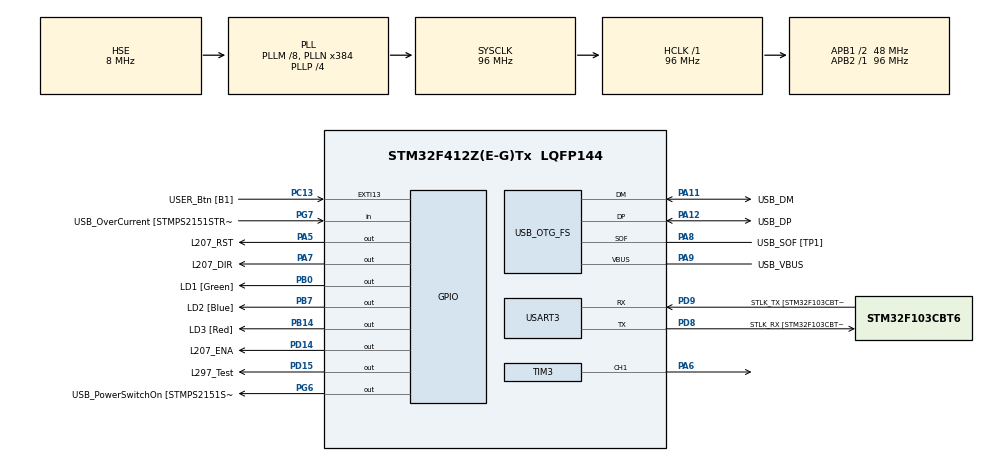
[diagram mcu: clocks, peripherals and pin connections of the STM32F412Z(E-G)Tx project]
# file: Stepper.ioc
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Mcu.Family=STM32F4
Mcu.Name=STM32F412Z(E-G)Tx
Mcu.Package=LQFP144
NVIC.PriorityGroup=NVIC_PRIORITYGROUP_4
NVIC.TIM3_IRQn=true\:0\:0\:false\:false\:true\:true\:true\:true
PA10.GPIO_Label=USB_ID
PA10.Signal=USB_OTG_FS_ID
PA11.GPIO_Label=USB_DM
PA11.Mode=Device_Only
PA11.Signal=USB_OTG_FS_DM
PA12.GPIO_Label=USB_DP
PA12.Mode=Device_Only
PA12.Signal=USB_OTG_FS_DP
PA13.GPIO_Label=TMS
PA13.Mode=Serial_Wire
PA13.Signal=SYS_JTMS-SWDIO
PA14.GPIO_Label=TCK
PA14.Mode=Serial_Wire
PA14.Signal=SYS_JTCK-SWCLK
PA5.GPIO_Label=L207_RST
PA5.Signal=GPIO_Output
PA6.Signal=S_TIM3_CH1
PA7.GPIO_Label=L207_DIR
PA7.Signal=GPIO_Output
PA8.GPIO_Label=USB_SOF [TP1]
PA8.Mode=Activate_SOF_FS
PA8.Signal=USB_OTG_FS_SOF
PA9.GPIO_Label=USB_VBUS
PA9.Mode=Activate_VBUS
PA9.Signal=USB_OTG_FS_VBUS
PB0.GPIO_Label=LD1 [Green]
PB0.Signal=GPIO_Output
PB14.GPIO_Label=LD3 [Red]
PB14.Signal=GPIO_Output
PB3.GPIO_Label=SWO
PB3.Signal=SYS_JTDO-SWO
PB7.GPIO_Label=LD2 [Blue]
PB7.Signal=GPIO_Output
PC13.GPIO_Label=USER_Btn [B1]
PC13.Signal=GPXTI13
PC14-OSC32_IN.Mode=LSE-External-Oscillator
PC14-OSC32_IN.Signal=RCC_OSC32_IN
PC15-OSC32_OUT.Mode=LSE-External-Oscillator
PC15-OSC32_OUT.Signal=RCC_OSC32_OUT
PD14.GPIO_Label=L207_ENA
PD14.Signal=GPIO_Output
PD15.GPIO_Label=L297_Test
PD15.Signal=GPIO_Output
PD8.GPIO_Label=STLK_RX [STM32F103CBT6_PA3]
PD8.Mode=Asynchronous
PD8.Signal=USART3_TX
PD9.GPIO_Label=STLK_TX [STM32F103CBT6_PA2]
PD9.Mode=Asynchronous
PD9.Signal=USART3_RX
PG6.GPIO_Label=USB_PowerSwitchOn [STMPS2151STR_EN]
PG6.Signal=GPIO_Output
PG7.GPIO_Label=USB_OverCurrent [STMPS2151STR_FAULT]
PG7.Signal=GPIO_Input
PH0\ -\ OSC_IN.GPIO_Label=MCO
PH0\ -\ OSC_IN.Mode=HSE-External-Clock-Source
PH0\ -\ OSC_IN.Signal=RCC_OSC_IN
PH1\ -\ OSC_OUT.Mode=HSE-External-Clock-Source
PH1\ -\ OSC_OUT.Signal=RCC_OSC_OUT
ProjectManager.HeapSize=0x400
ProjectManager.StackSize=0x800
ProjectManager.TargetToolchain=STM32CubeIDE
RCC.48MHZClocksFreq_Value=24000000
RCC.AHBFreq_Value=96000000
RCC.APB1CLKDivider=RCC_HCLK_DIV2
RCC.APB1Freq_Value=48000000
RCC.APB1TimFreq_Value=96000000
RCC.APB2Freq_Value=96000000
RCC.APB2TimFreq_Value=96000000
RCC.CortexFreq_Value=96000000
RCC.HCLKFreq_Value=96000000
RCC.HSE_VALUE=8000000
RCC.HSI_VALUE=16000000
RCC.PLLM=8
RCC.PLLMUL=RCC_PLL_MUL9
RCC.PLLN=384
RCC.PLLP=RCC_PLLP_DIV4
RCC.PLLQ=8
RCC.PRESCALERUSB=RCC_USBCLKSOURCE_PLL_DIV1_5
RCC.SYSCLKFreq_VALUE=96000000
RCC.SYSCLKSource=RCC_SYSCLKSOURCE_PLLCLK
RCC.SYSCLKSourceVirtual=RCC_SYSCLKSOURCE_PLLCLK
RCC.USBFreq_Value=48000000
RCC.VCOOutputFreq_Value=384000000
SH.S_TIM3_CH1.0=TIM3_CH1,PWM Generation1 CH1
TIM3.Channel-PWM\ Generation1\ CH1=TIM_CHANNEL_1
TIM3.Period=1000
TIM3.Prescaler=95
USART3.VirtualMode=VM_ASYNC
USB_OTG_FS.VirtualMode=Device_Only
board=NUCLEO-F412ZG

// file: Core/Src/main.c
/* USER CODE BEGIN Header */
/**
  ******************************************************************************
  * @file           : main.c
  * @brief          : Main program body
  ******************************************************************************
  * @attention
  *
  * Copyright (c) 2023 STMicroelectronics.
  * All rights reserved.
  *
  * This software is licensed under terms that can be found in the LICENSE file
  * in the root directory of this software component.
  * If no LICENSE file comes with this software, it is provided AS-IS.
  *
  ******************************************************************************
  */
/* USER CODE END Header */
#include "main.h"

TIM_HandleTypeDef htim3;

UART_HandleTypeDef huart3;

PCD_HandleTypeDef hpcd_USB_OTG_FS;

void SystemClock_Config(void);
static void MX_GPIO_Init(void);
static void MX_USART3_UART_Init(void);
static void MX_USB_OTG_FS_PCD_Init(void);
static void MX_TIM3_Init(void);

int main(void)
{

  /* MCU Configuration--------------------------------------------------------*/

  /* Reset of all peripherals, Initializes the Flash interface and the Systick. */
  HAL_Init();

  /* Configure the system clock */
  SystemClock_Config();

  /* Initialize all configured peripherals */
  MX_GPIO_Init();
  MX_USART3_UART_Init();
  MX_USB_OTG_FS_PCD_Init();
  MX_TIM3_Init();

  /* Infinite loop */
  while (1)
  {

  }
}

void SystemClock_Config(void)
{
  RCC_OscInitTypeDef RCC_OscInitStruct = {0};
  RCC_ClkInitTypeDef RCC_ClkInitStruct = {0};

  /** Configure the main internal regulator output voltage
  */
  __HAL_RCC_PWR_CLK_ENABLE();
  __HAL_PWR_VOLTAGESCALING_CONFIG(PWR_REGULATOR_VOLTAGE_SCALE1);

  /** Initializes the RCC Oscillators according to the specified parameters
  * in the RCC_OscInitTypeDef structure.
  */
  RCC_OscInitStruct.OscillatorType = RCC_OSCILLATORTYPE_HSE;
  RCC_OscInitStruct.HSEState = RCC_HSE_BYPASS;
  RCC_OscInitStruct.PLL.PLLState = RCC_PLL_ON;
  RCC_OscInitStruct.PLL.PLLSource = RCC_PLLSOURCE_HSE;
  RCC_OscInitStruct.PLL.PLLM = 8;
  RCC_OscInitStruct.PLL.PLLN = 384;
  RCC_OscInitStruct.PLL.PLLP = RCC_PLLP_DIV4;
  RCC_OscInitStruct.PLL.PLLQ = 8;
  RCC_OscInitStruct.PLL.PLLR = 2;
  if (HAL_RCC_OscConfig(&RCC_OscInitStruct) != HAL_OK)
  {
    Error_Handler();
  }

  /** Initializes the CPU, AHB and APB buses clocks
  */
  RCC_ClkInitStruct.ClockType = RCC_CLOCKTYPE_HCLK|RCC_CLOCKTYPE_SYSCLK
                              |RCC_CLOCKTYPE_PCLK1|RCC_CLOCKTYPE_PCLK2;
  RCC_ClkInitStruct.SYSCLKSource = RCC_SYSCLKSOURCE_PLLCLK;
  RCC_ClkInitStruct.AHBCLKDivider = RCC_SYSCLK_DIV1;
  RCC_ClkInitStruct.APB1CLKDivider = RCC_HCLK_DIV2;
  RCC_ClkInitStruct.APB2CLKDivider = RCC_HCLK_DIV1;

  if (HAL_RCC_ClockConfig(&RCC_ClkInitStruct, FLASH_LATENCY_3) != HAL_OK)
  {
    Error_Handler();
  }
}

static void MX_TIM3_Init(void)
{

  TIM_MasterConfigTypeDef sMasterConfig = {0};
  TIM_OC_InitTypeDef sConfigOC = {0};

  htim3.Instance = TIM3;
  htim3.Init.Prescaler = 0;
  htim3.Init.CounterMode = TIM_COUNTERMODE_UP;
  htim3.Init.Period = 65535;
  htim3.Init.ClockDivision = TIM_CLOCKDIVISION_DIV1;
  htim3.Init.AutoReloadPreload = TIM_AUTORELOAD_PRELOAD_DISABLE;
  if (HAL_TIM_PWM_Init(&htim3) != HAL_OK)
  {
    Error_Handler();
  }
  sMasterConfig.MasterOutputTrigger = TIM_TRGO_RESET;
  sMasterConfig.MasterSlaveMode = TIM_MASTERSLAVEMODE_DISABLE;
  if (HAL_TIMEx_MasterConfigSynchronization(&htim3, &sMasterConfig) != HAL_OK)
  {
    Error_Handler();
  }
  sConfigOC.OCMode = TIM_OCMODE_PWM1;
  sConfigOC.Pulse = 0;
  sConfigOC.OCPolarity = TIM_OCPOLARITY_HIGH;
  sConfigOC.OCFastMode = TIM_OCFAST_DISABLE;
  if (HAL_TIM_PWM_ConfigChannel(&htim3, &sConfigOC, TIM_CHANNEL_1) != HAL_OK)
  {
    Error_Handler();
  }
  HAL_TIM_MspPostInit(&htim3);

}

static void MX_USART3_UART_Init(void)
{

  huart3.Instance = USART3;
  huart3.Init.BaudRate = 115200;
  huart3.Init.WordLength = UART_WORDLENGTH_8B;
  huart3.Init.StopBits = UART_STOPBITS_1;
  huart3.Init.Parity = UART_PARITY_NONE;
  huart3.Init.Mode = UART_MODE_TX_RX;
  huart3.Init.HwFlowCtl = UART_HWCONTROL_NONE;
  huart3.Init.OverSampling = UART_OVERSAMPLING_16;
  if (HAL_UART_Init(&huart3) != HAL_OK)
  {
    Error_Handler();
  }

}

static void MX_USB_OTG_FS_PCD_Init(void)
{

  hpcd_USB_OTG_FS.Instance = USB_OTG_FS;
  hpcd_USB_OTG_FS.Init.dev_endpoints = 6;
  hpcd_USB_OTG_FS.Init.speed = PCD_SPEED_FULL;
  hpcd_USB_OTG_FS.Init.dma_enable = DISABLE;
  hpcd_USB_OTG_FS.Init.phy_itface = PCD_PHY_EMBEDDED;
  hpcd_USB_OTG_FS.Init.Sof_enable = ENABLE;
  hpcd_USB_OTG_FS.Init.low_power_enable = DISABLE;
  hpcd_USB_OTG_FS.Init.lpm_enable = DISABLE;
  hpcd_USB_OTG_FS.Init.battery_charging_enable = ENABLE;
  hpcd_USB_OTG_FS.Init.vbus_sensing_enable = ENABLE;
  hpcd_USB_OTG_FS.Init.use_dedicated_ep1 = DISABLE;
  if (HAL_PCD_Init(&hpcd_USB_OTG_FS) != HAL_OK)
  {
    Error_Handler();
  }

}

static void MX_GPIO_Init(void)
{
  GPIO_InitTypeDef GPIO_InitStruct = {0};

  /* GPIO Ports Clock Enable */
  __HAL_RCC_GPIOC_CLK_ENABLE();
  __HAL_RCC_GPIOH_CLK_ENABLE();
  __HAL_RCC_GPIOA_CLK_ENABLE();
  __HAL_RCC_GPIOB_CLK_ENABLE();
  __HAL_RCC_GPIOF_CLK_ENABLE();
  __HAL_RCC_GPIOD_CLK_ENABLE();
  __HAL_RCC_GPIOG_CLK_ENABLE();

  /*Configure GPIO pin Output Level */
  HAL_GPIO_WritePin(L297_PULSE_GPIO_Port, L297_PULSE_Pin, GPIO_PIN_RESET);

  /*Configure GPIO pin Output Level */
  HAL_GPIO_WritePin(GPIOB, LD1_Pin|LD3_Pin|LD2_Pin, GPIO_PIN_RESET);

  /*Configure GPIO pin Output Level */
  HAL_GPIO_WritePin(L297_RST_GPIO_Port, L297_RST_Pin, GPIO_PIN_RESET);

  /*Configure GPIO pin Output Level */
  HAL_GPIO_WritePin(GPIOD, L297_DIR_Pin|L297_ENA_Pin, GPIO_PIN_RESET);

  /*Configure GPIO pin Output Level */
  HAL_GPIO_WritePin(USB_PowerSwitchOn_GPIO_Port, USB_PowerSwitchOn_Pin, GPIO_PIN_RESET);

  /*Configure GPIO pin : BLUE_BTN_Pin */
  GPIO_InitStruct.Pin = BLUE_BTN_Pin;
  GPIO_InitStruct.Mode = GPIO_MODE_IT_RISING;
  GPIO_InitStruct.Pull = GPIO_NOPULL;
  HAL_GPIO_Init(BLUE_BTN_GPIO_Port, &GPIO_InitStruct);

  /*Configure GPIO pin : L297_PULSE_Pin */
  GPIO_InitStruct.Pin = L297_PULSE_Pin;
  GPIO_InitStruct.Mode = GPIO_MODE_OUTPUT_PP;
  GPIO_InitStruct.Pull = GPIO_NOPULL;
  GPIO_InitStruct.Speed = GPIO_SPEED_FREQ_LOW;
  HAL_GPIO_Init(L297_PULSE_GPIO_Port, &GPIO_InitStruct);

  /*Configure GPIO pins : LD1_Pin LD3_Pin LD2_Pin */
  GPIO_InitStruct.Pin = LD1_Pin|LD3_Pin|LD2_Pin;
  GPIO_InitStruct.Mode = GPIO_MODE_OUTPUT_PP;
  GPIO_InitStruct.Pull = GPIO_NOPULL;
  GPIO_InitStruct.Speed = GPIO_SPEED_FREQ_LOW;
  HAL_GPIO_Init(GPIOB, &GPIO_InitStruct);

  /*Configure GPIO pin : L297_RST_Pin */
  GPIO_InitStruct.Pin = L297_RST_Pin;
  GPIO_InitStruct.Mode = GPIO_MODE_OUTPUT_PP;
  GPIO_InitStruct.Pull = GPIO_NOPULL;
  GPIO_InitStruct.Speed = GPIO_SPEED_FREQ_LOW;
  HAL_GPIO_Init(L297_RST_GPIO_Port, &GPIO_InitStruct);

  /*Configure GPIO pins : L297_DIR_Pin L297_ENA_Pin */
  GPIO_InitStruct.Pin = L297_DIR_Pin|L297_ENA_Pin;
  GPIO_InitStruct.Mode = GPIO_MODE_OUTPUT_PP;
  GPIO_InitStruct.Pull = GPIO_NOPULL;
  GPIO_InitStruct.Speed = GPIO_SPEED_FREQ_LOW;
  HAL_GPIO_Init(GPIOD, &GPIO_InitStruct);

  /*Configure GPIO pin : USB_PowerSwitchOn_Pin */
  GPIO_InitStruct.Pin = USB_PowerSwitchOn_Pin;
  GPIO_InitStruct.Mode = GPIO_MODE_OUTPUT_PP;
  GPIO_InitStruct.Pull = GPIO_NOPULL;
  GPIO_InitStruct.Speed = GPIO_SPEED_FREQ_LOW;
  HAL_GPIO_Init(USB_PowerSwitchOn_GPIO_Port, &GPIO_InitStruct);

  /*Configure GPIO pin : USB_OverCurrent_Pin */
  GPIO_InitStruct.Pin = USB_OverCurrent_Pin;
  GPIO_InitStruct.Mode = GPIO_MODE_INPUT;
  GPIO_InitStruct.Pull = GPIO_NOPULL;
  HAL_GPIO_Init(USB_OverCurrent_GPIO_Port, &GPIO_InitStruct);

  /* EXTI interrupt init*/
  HAL_NVIC_SetPriority(EXTI15_10_IRQn, 0, 0);
  HAL_NVIC_EnableIRQ(EXTI15_10_IRQn);

}

void Error_Handler(void)
{
  __disable_irq();
  while (1)
  {
  }
}
